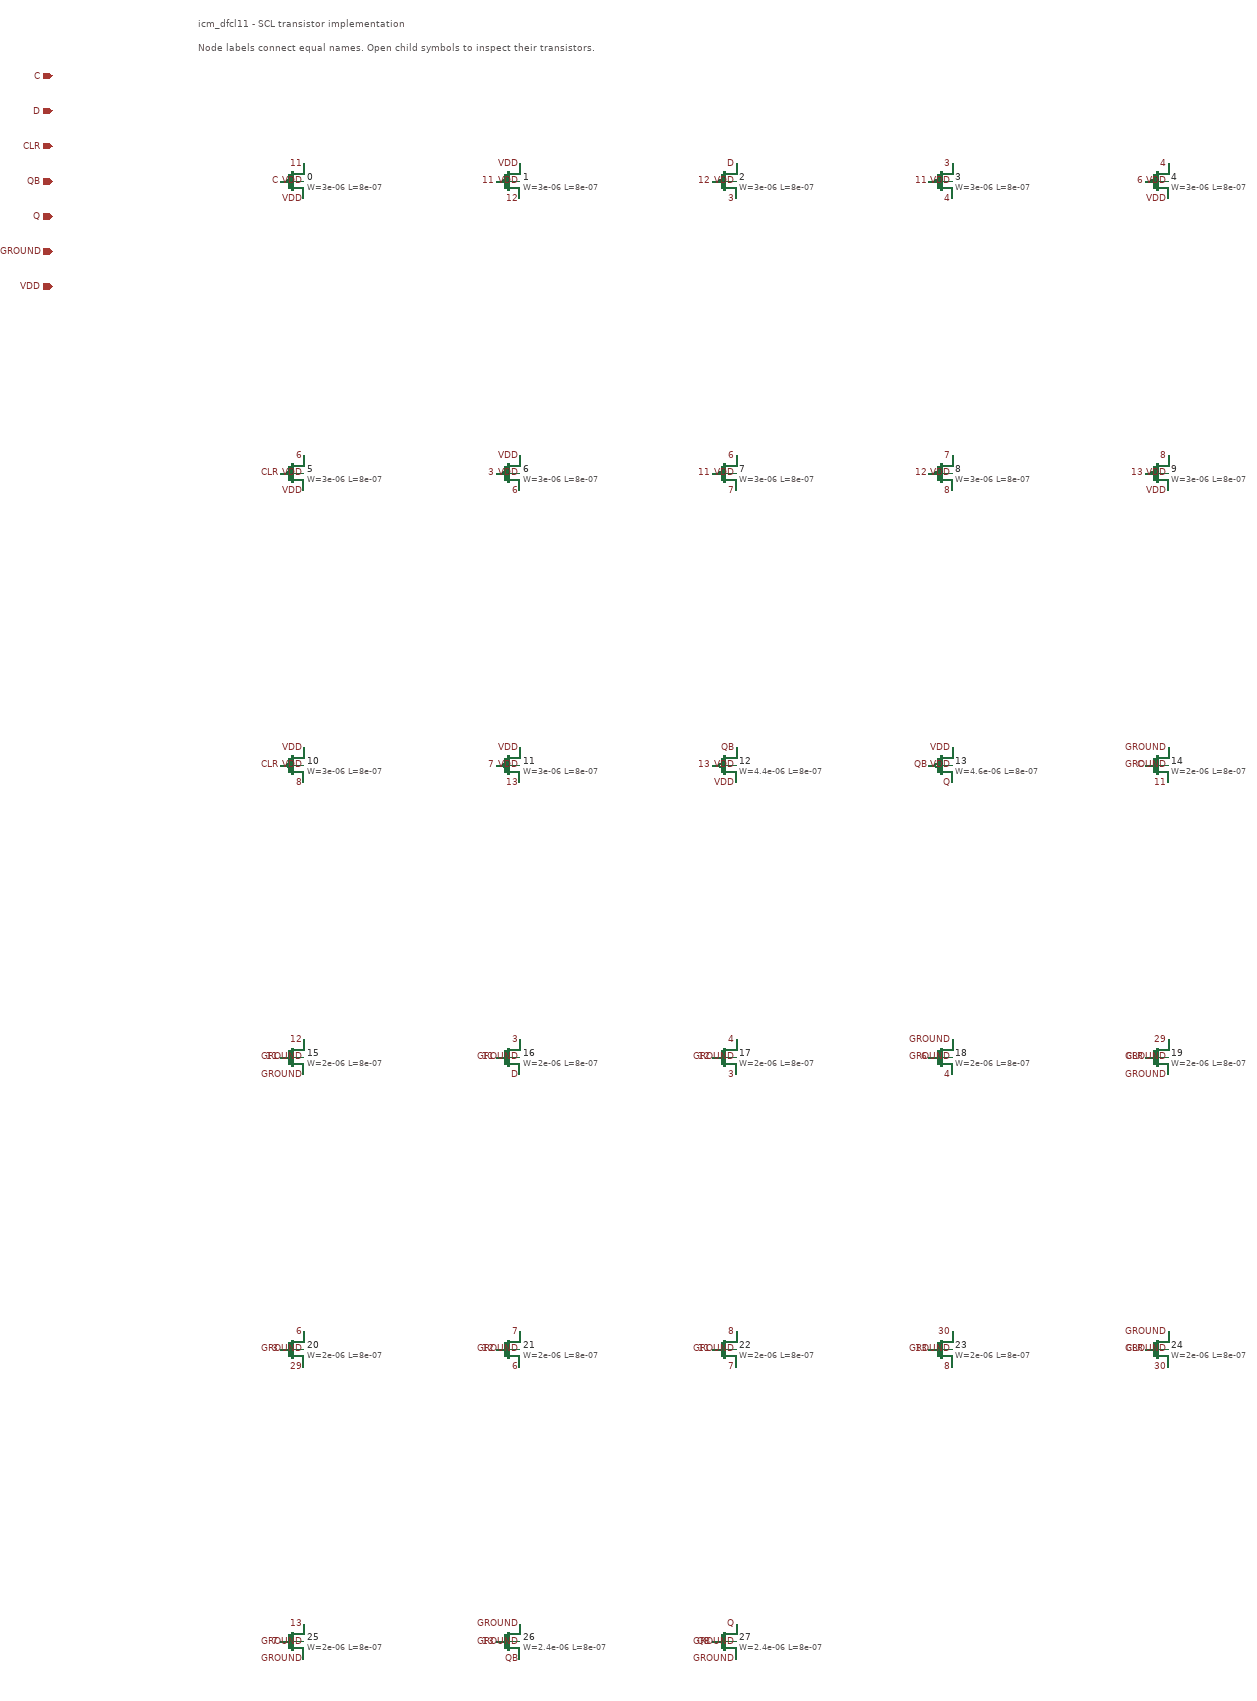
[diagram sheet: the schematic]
v {xschem version=3.4.5 file_version=1.2}
G {}
K {}
V {}
S {}
E {}
T {icm_dfcl11 - SCL transistor implementation} 0 -100 0 0 .5 .5 {}
T {Node labels connect equal names. Open child symbols to inspect their transistors.} 0 -60 0 0 .25 .25 {}
C {/usr/share/xschem/xschem_library/devices/iopin.sym} -250 0 0 0 {name=P0 lab=C}
C {/usr/share/xschem/xschem_library/devices/iopin.sym} -250 60 0 0 {name=P1 lab=D}
C {/usr/share/xschem/xschem_library/devices/iopin.sym} -250 120 0 0 {name=P2 lab=CLR}
C {/usr/share/xschem/xschem_library/devices/iopin.sym} -250 180 0 0 {name=P3 lab=QB}
C {/usr/share/xschem/xschem_library/devices/iopin.sym} -250 240 0 0 {name=P4 lab=Q}
C {/usr/share/xschem/xschem_library/devices/iopin.sym} -250 300 0 0 {name=P5 lab=GROUND}
C {/usr/share/xschem/xschem_library/devices/iopin.sym} -250 360 0 0 {name=P6 lab=VDD}
C {/home/shreyas/open_source_scl_cp8d/open_pdks/scl_cp8d/libs.tech/xschem/scl_pcell/pmos4_p_cp8d.sym} 160 180 0 0 {name=0 model=P W="3e-06" L="8e-07" nf=1 mult="1" ad="9.6e-12" as="8.7e-12" pd="1.24e-05" ps="1.18e-05" nrd=0.366667 nrs=0.533333}
C {/usr/share/xschem/xschem_library/devices/lab_pin.sym} 180 210 0 0 {name=L1 lab=VDD}
C {/usr/share/xschem/xschem_library/devices/lab_pin.sym} 140 180 0 0 {name=L2 lab=C}
C {/usr/share/xschem/xschem_library/devices/lab_pin.sym} 180 150 0 0 {name=L3 lab=11}
C {/usr/share/xschem/xschem_library/devices/lab_pin.sym} 180 180 0 0 {name=L4 lab=VDD}
C {/home/shreyas/open_source_scl_cp8d/open_pdks/scl_cp8d/libs.tech/xschem/scl_pcell/pmos4_p_cp8d.sym} 530 180 0 0 {name=1 model=P W="3e-06" L="8e-07" nf=1 mult="1" ad="8.7e-12" as="9.6e-12" pd="1.18e-05" ps="1.24e-05" nrd=0.366667 nrs=0.533333}
C {/usr/share/xschem/xschem_library/devices/lab_pin.sym} 550 210 0 0 {name=L5 lab=12}
C {/usr/share/xschem/xschem_library/devices/lab_pin.sym} 510 180 0 0 {name=L6 lab=11}
C {/usr/share/xschem/xschem_library/devices/lab_pin.sym} 550 150 0 0 {name=L7 lab=VDD}
C {/usr/share/xschem/xschem_library/devices/lab_pin.sym} 550 180 0 0 {name=L8 lab=VDD}
C {/home/shreyas/open_source_scl_cp8d/open_pdks/scl_cp8d/libs.tech/xschem/scl_pcell/pmos4_p_cp8d.sym} 900 180 0 0 {name=2 model=P W="3e-06" L="8e-07" nf=1 mult="1" ad="1.05e-11" as="8.7e-12" pd="1.3e-05" ps="1.18e-05" nrd=0.391667 nrs=0.533333}
C {/usr/share/xschem/xschem_library/devices/lab_pin.sym} 920 210 0 0 {name=L9 lab=3}
C {/usr/share/xschem/xschem_library/devices/lab_pin.sym} 880 180 0 0 {name=L10 lab=12}
C {/usr/share/xschem/xschem_library/devices/lab_pin.sym} 920 150 0 0 {name=L11 lab=D}
C {/usr/share/xschem/xschem_library/devices/lab_pin.sym} 920 180 0 0 {name=L12 lab=VDD}
C {/home/shreyas/open_source_scl_cp8d/open_pdks/scl_cp8d/libs.tech/xschem/scl_pcell/pmos4_p_cp8d.sym} 1270 180 0 0 {name=3 model=P W="3e-06" L="8e-07" nf=1 mult="1" ad="1.08e-11" as="1.05e-11" pd="1.32e-05" ps="1.3e-05" nrd=0.408333 nrs=0.583333}
C {/usr/share/xschem/xschem_library/devices/lab_pin.sym} 1290 210 0 0 {name=L13 lab=4}
C {/usr/share/xschem/xschem_library/devices/lab_pin.sym} 1250 180 0 0 {name=L14 lab=11}
C {/usr/share/xschem/xschem_library/devices/lab_pin.sym} 1290 150 0 0 {name=L15 lab=3}
C {/usr/share/xschem/xschem_library/devices/lab_pin.sym} 1290 180 0 0 {name=L16 lab=VDD}
C {/home/shreyas/open_source_scl_cp8d/open_pdks/scl_cp8d/libs.tech/xschem/scl_pcell/pmos4_p_cp8d.sym} 1640 180 0 0 {name=4 model=P W="3e-06" L="8e-07" nf=1 mult="1" ad="8.7e-12" as="1.08e-11" pd="1.18e-05" ps="1.32e-05" nrd=0.366667 nrs=0.583333}
C {/usr/share/xschem/xschem_library/devices/lab_pin.sym} 1660 210 0 0 {name=L17 lab=VDD}
C {/usr/share/xschem/xschem_library/devices/lab_pin.sym} 1620 180 0 0 {name=L18 lab=6}
C {/usr/share/xschem/xschem_library/devices/lab_pin.sym} 1660 150 0 0 {name=L19 lab=4}
C {/usr/share/xschem/xschem_library/devices/lab_pin.sym} 1660 180 0 0 {name=L20 lab=VDD}
C {/home/shreyas/open_source_scl_cp8d/open_pdks/scl_cp8d/libs.tech/xschem/scl_pcell/pmos4_p_cp8d.sym} 160 680 0 0 {name=5 model=P W="3e-06" L="8e-07" nf=1 mult="1" ad="9.6e-12" as="8.7e-12" pd="1.24e-05" ps="1.18e-05" nrd=0.366667 nrs=0.533333}
C {/usr/share/xschem/xschem_library/devices/lab_pin.sym} 180 710 0 0 {name=L21 lab=VDD}
C {/usr/share/xschem/xschem_library/devices/lab_pin.sym} 140 680 0 0 {name=L22 lab=CLR}
C {/usr/share/xschem/xschem_library/devices/lab_pin.sym} 180 650 0 0 {name=L23 lab=6}
C {/usr/share/xschem/xschem_library/devices/lab_pin.sym} 180 680 0 0 {name=L24 lab=VDD}
C {/home/shreyas/open_source_scl_cp8d/open_pdks/scl_cp8d/libs.tech/xschem/scl_pcell/pmos4_p_cp8d.sym} 530 680 0 0 {name=6 model=P W="3e-06" L="8e-07" nf=1 mult="1" ad="1.08e-11" as="9.6e-12" pd="1.32e-05" ps="1.24e-05" nrd=0.391667 nrs=0.533333}
C {/usr/share/xschem/xschem_library/devices/lab_pin.sym} 550 710 0 0 {name=L25 lab=6}
C {/usr/share/xschem/xschem_library/devices/lab_pin.sym} 510 680 0 0 {name=L26 lab=3}
C {/usr/share/xschem/xschem_library/devices/lab_pin.sym} 550 650 0 0 {name=L27 lab=VDD}
C {/usr/share/xschem/xschem_library/devices/lab_pin.sym} 550 680 0 0 {name=L28 lab=VDD}
C {/home/shreyas/open_source_scl_cp8d/open_pdks/scl_cp8d/libs.tech/xschem/scl_pcell/pmos4_p_cp8d.sym} 900 680 0 0 {name=7 model=P W="3e-06" L="8e-07" nf=1 mult="1" ad="1.08e-11" as="1.08e-11" pd="1.32e-05" ps="1.32e-05" nrd=0.391667 nrs=0.616667}
C {/usr/share/xschem/xschem_library/devices/lab_pin.sym} 920 710 0 0 {name=L29 lab=7}
C {/usr/share/xschem/xschem_library/devices/lab_pin.sym} 880 680 0 0 {name=L30 lab=11}
C {/usr/share/xschem/xschem_library/devices/lab_pin.sym} 920 650 0 0 {name=L31 lab=6}
C {/usr/share/xschem/xschem_library/devices/lab_pin.sym} 920 680 0 0 {name=L32 lab=VDD}
C {/home/shreyas/open_source_scl_cp8d/open_pdks/scl_cp8d/libs.tech/xschem/scl_pcell/pmos4_p_cp8d.sym} 1270 680 0 0 {name=8 model=P W="3e-06" L="8e-07" nf=1 mult="1" ad="1.05e-11" as="1.08e-11" pd="1.3e-05" ps="1.32e-05" nrd=0.391667 nrs=0.616667}
C {/usr/share/xschem/xschem_library/devices/lab_pin.sym} 1290 710 0 0 {name=L33 lab=8}
C {/usr/share/xschem/xschem_library/devices/lab_pin.sym} 1250 680 0 0 {name=L34 lab=12}
C {/usr/share/xschem/xschem_library/devices/lab_pin.sym} 1290 650 0 0 {name=L35 lab=7}
C {/usr/share/xschem/xschem_library/devices/lab_pin.sym} 1290 680 0 0 {name=L36 lab=VDD}
C {/home/shreyas/open_source_scl_cp8d/open_pdks/scl_cp8d/libs.tech/xschem/scl_pcell/pmos4_p_cp8d.sym} 1640 680 0 0 {name=9 model=P W="3e-06" L="8e-07" nf=1 mult="1" ad="9.6e-12" as="1.05e-11" pd="1.24e-05" ps="1.3e-05" nrd=0.366667 nrs=0.583333}
C {/usr/share/xschem/xschem_library/devices/lab_pin.sym} 1660 710 0 0 {name=L37 lab=VDD}
C {/usr/share/xschem/xschem_library/devices/lab_pin.sym} 1620 680 0 0 {name=L38 lab=13}
C {/usr/share/xschem/xschem_library/devices/lab_pin.sym} 1660 650 0 0 {name=L39 lab=8}
C {/usr/share/xschem/xschem_library/devices/lab_pin.sym} 1660 680 0 0 {name=L40 lab=VDD}
C {/home/shreyas/open_source_scl_cp8d/open_pdks/scl_cp8d/libs.tech/xschem/scl_pcell/pmos4_p_cp8d.sym} 160 1180 0 0 {name=10 model=P W="3e-06" L="8e-07" nf=1 mult="1" ad="8.7e-12" as="9.6e-12" pd="1.18e-05" ps="1.24e-05" nrd=0.366667 nrs=0.533333}
C {/usr/share/xschem/xschem_library/devices/lab_pin.sym} 180 1210 0 0 {name=L41 lab=8}
C {/usr/share/xschem/xschem_library/devices/lab_pin.sym} 140 1180 0 0 {name=L42 lab=CLR}
C {/usr/share/xschem/xschem_library/devices/lab_pin.sym} 180 1150 0 0 {name=L43 lab=VDD}
C {/usr/share/xschem/xschem_library/devices/lab_pin.sym} 180 1180 0 0 {name=L44 lab=VDD}
C {/home/shreyas/open_source_scl_cp8d/open_pdks/scl_cp8d/libs.tech/xschem/scl_pcell/pmos4_p_cp8d.sym} 530 1180 0 0 {name=11 model=P W="3e-06" L="8e-07" nf=1 mult="1" ad="8.7e-12" as="8.7e-12" pd="1.18e-05" ps="1.18e-05" nrd=0.366667 nrs=0.533333}
C {/usr/share/xschem/xschem_library/devices/lab_pin.sym} 550 1210 0 0 {name=L45 lab=13}
C {/usr/share/xschem/xschem_library/devices/lab_pin.sym} 510 1180 0 0 {name=L46 lab=7}
C {/usr/share/xschem/xschem_library/devices/lab_pin.sym} 550 1150 0 0 {name=L47 lab=VDD}
C {/usr/share/xschem/xschem_library/devices/lab_pin.sym} 550 1180 0 0 {name=L48 lab=VDD}
C {/home/shreyas/open_source_scl_cp8d/open_pdks/scl_cp8d/libs.tech/xschem/scl_pcell/pmos4_p_cp8d.sym} 900 1180 0 0 {name=12 model=P W="4.4e-06" L="8e-07" nf=1 mult="1" ad="1.441e-11" as="1.276e-11" pd="1.56e-05" ps="1.46e-05" nrd=0.25 nrs=0.363636}
C {/usr/share/xschem/xschem_library/devices/lab_pin.sym} 920 1210 0 0 {name=L49 lab=VDD}
C {/usr/share/xschem/xschem_library/devices/lab_pin.sym} 880 1180 0 0 {name=L50 lab=13}
C {/usr/share/xschem/xschem_library/devices/lab_pin.sym} 920 1150 0 0 {name=L51 lab=QB}
C {/usr/share/xschem/xschem_library/devices/lab_pin.sym} 920 1180 0 0 {name=L52 lab=VDD}
C {/home/shreyas/open_source_scl_cp8d/open_pdks/scl_cp8d/libs.tech/xschem/scl_pcell/pmos4_p_cp8d.sym} 1270 1180 0 0 {name=13 model=P W="4.6e-06" L="8e-07" nf=1 mult="1" ad="1.334e-11" as="1.441e-11" pd="1.5e-05" ps="1.56e-05" nrd=0.23913 nrs=0.347826}
C {/usr/share/xschem/xschem_library/devices/lab_pin.sym} 1290 1210 0 0 {name=L53 lab=Q}
C {/usr/share/xschem/xschem_library/devices/lab_pin.sym} 1250 1180 0 0 {name=L54 lab=QB}
C {/usr/share/xschem/xschem_library/devices/lab_pin.sym} 1290 1150 0 0 {name=L55 lab=VDD}
C {/usr/share/xschem/xschem_library/devices/lab_pin.sym} 1290 1180 0 0 {name=L56 lab=VDD}
C {/home/shreyas/open_source_scl_cp8d/open_pdks/scl_cp8d/libs.tech/xschem/scl_pcell/nmos4_n_cp8d.sym} 1640 1180 0 0 {name=14 model=N W="2e-06" L="8e-07" nf=1 mult="1" ad="8.24e-12" as="7.5e-12" pd="1.2e-05" ps="1.12e-05" nrd=0.575 nrs=0.85}
C {/usr/share/xschem/xschem_library/devices/lab_pin.sym} 1660 1150 0 0 {name=L57 lab=GROUND}
C {/usr/share/xschem/xschem_library/devices/lab_pin.sym} 1620 1180 0 0 {name=L58 lab=C}
C {/usr/share/xschem/xschem_library/devices/lab_pin.sym} 1660 1210 0 0 {name=L59 lab=11}
C {/usr/share/xschem/xschem_library/devices/lab_pin.sym} 1660 1180 0 0 {name=L60 lab=GROUND}
C {/home/shreyas/open_source_scl_cp8d/open_pdks/scl_cp8d/libs.tech/xschem/scl_pcell/nmos4_n_cp8d.sym} 160 1680 0 0 {name=15 model=N W="2e-06" L="8e-07" nf=1 mult="1" ad="7.5e-12" as="8.24e-12" pd="1.12e-05" ps="1.2e-05" nrd=0.575 nrs=0.85}
C {/usr/share/xschem/xschem_library/devices/lab_pin.sym} 180 1650 0 0 {name=L61 lab=12}
C {/usr/share/xschem/xschem_library/devices/lab_pin.sym} 140 1680 0 0 {name=L62 lab=11}
C {/usr/share/xschem/xschem_library/devices/lab_pin.sym} 180 1710 0 0 {name=L63 lab=GROUND}
C {/usr/share/xschem/xschem_library/devices/lab_pin.sym} 180 1680 0 0 {name=L64 lab=GROUND}
C {/home/shreyas/open_source_scl_cp8d/open_pdks/scl_cp8d/libs.tech/xschem/scl_pcell/nmos4_n_cp8d.sym} 530 1680 0 0 {name=16 model=N W="2e-06" L="8e-07" nf=1 mult="1" ad="8.76e-12" as="7.5e-12" pd="1.24e-05" ps="1.12e-05" nrd=0.6 nrs=0.85}
C {/usr/share/xschem/xschem_library/devices/lab_pin.sym} 550 1650 0 0 {name=L65 lab=3}
C {/usr/share/xschem/xschem_library/devices/lab_pin.sym} 510 1680 0 0 {name=L66 lab=11}
C {/usr/share/xschem/xschem_library/devices/lab_pin.sym} 550 1710 0 0 {name=L67 lab=D}
C {/usr/share/xschem/xschem_library/devices/lab_pin.sym} 550 1680 0 0 {name=L68 lab=GROUND}
C {/home/shreyas/open_source_scl_cp8d/open_pdks/scl_cp8d/libs.tech/xschem/scl_pcell/nmos4_n_cp8d.sym} 900 1680 0 0 {name=17 model=N W="2e-06" L="8e-07" nf=1 mult="1" ad="3.056e-11" as="8.76e-12" pd="2.34e-05" ps="1.24e-05" nrd=0.9 nrs=0.9}
C {/usr/share/xschem/xschem_library/devices/lab_pin.sym} 920 1650 0 0 {name=L69 lab=4}
C {/usr/share/xschem/xschem_library/devices/lab_pin.sym} 880 1680 0 0 {name=L70 lab=12}
C {/usr/share/xschem/xschem_library/devices/lab_pin.sym} 920 1710 0 0 {name=L71 lab=3}
C {/usr/share/xschem/xschem_library/devices/lab_pin.sym} 920 1680 0 0 {name=L72 lab=GROUND}
C {/home/shreyas/open_source_scl_cp8d/open_pdks/scl_cp8d/libs.tech/xschem/scl_pcell/nmos4_n_cp8d.sym} 1270 1680 0 0 {name=18 model=N W="2e-06" L="8e-07" nf=1 mult="1" ad="2.236e-11" as="3.056e-11" pd="2.42e-05" ps="2.34e-05" nrd=0.9 nrs=0.9}
C {/usr/share/xschem/xschem_library/devices/lab_pin.sym} 1290 1650 0 0 {name=L73 lab=GROUND}
C {/usr/share/xschem/xschem_library/devices/lab_pin.sym} 1250 1680 0 0 {name=L74 lab=6}
C {/usr/share/xschem/xschem_library/devices/lab_pin.sym} 1290 1710 0 0 {name=L75 lab=4}
C {/usr/share/xschem/xschem_library/devices/lab_pin.sym} 1290 1680 0 0 {name=L76 lab=GROUND}
C {/home/shreyas/open_source_scl_cp8d/open_pdks/scl_cp8d/libs.tech/xschem/scl_pcell/nmos4_n_cp8d.sym} 1640 1680 0 0 {name=19 model=N W="2e-06" L="8e-07" nf=1 mult="1" ad="3.2e-12" as="2.236e-11" pd="5.2e-06" ps="2.42e-05" nrd=0.8 nrs=0.9}
C {/usr/share/xschem/xschem_library/devices/lab_pin.sym} 1660 1650 0 0 {name=L77 lab=29}
C {/usr/share/xschem/xschem_library/devices/lab_pin.sym} 1620 1680 0 0 {name=L78 lab=CLR}
C {/usr/share/xschem/xschem_library/devices/lab_pin.sym} 1660 1710 0 0 {name=L79 lab=GROUND}
C {/usr/share/xschem/xschem_library/devices/lab_pin.sym} 1660 1680 0 0 {name=L80 lab=GROUND}
C {/home/shreyas/open_source_scl_cp8d/open_pdks/scl_cp8d/libs.tech/xschem/scl_pcell/nmos4_n_cp8d.sym} 160 2180 0 0 {name=20 model=N W="2e-06" L="8e-07" nf=1 mult="1" ad="8.76e-12" as="3.2e-12" pd="1.24e-05" ps="5.2e-06" nrd=0.9 nrs=0.8}
C {/usr/share/xschem/xschem_library/devices/lab_pin.sym} 180 2150 0 0 {name=L81 lab=6}
C {/usr/share/xschem/xschem_library/devices/lab_pin.sym} 140 2180 0 0 {name=L82 lab=3}
C {/usr/share/xschem/xschem_library/devices/lab_pin.sym} 180 2210 0 0 {name=L83 lab=29}
C {/usr/share/xschem/xschem_library/devices/lab_pin.sym} 180 2180 0 0 {name=L84 lab=GROUND}
C {/home/shreyas/open_source_scl_cp8d/open_pdks/scl_cp8d/libs.tech/xschem/scl_pcell/nmos4_n_cp8d.sym} 530 2180 0 0 {name=21 model=N W="2e-06" L="8e-07" nf=1 mult="1" ad="8.76e-12" as="8.76e-12" pd="1.24e-05" ps="1.24e-05" nrd=0.6 nrs=0.9}
C {/usr/share/xschem/xschem_library/devices/lab_pin.sym} 550 2150 0 0 {name=L85 lab=7}
C {/usr/share/xschem/xschem_library/devices/lab_pin.sym} 510 2180 0 0 {name=L86 lab=12}
C {/usr/share/xschem/xschem_library/devices/lab_pin.sym} 550 2210 0 0 {name=L87 lab=6}
C {/usr/share/xschem/xschem_library/devices/lab_pin.sym} 550 2180 0 0 {name=L88 lab=GROUND}
C {/home/shreyas/open_source_scl_cp8d/open_pdks/scl_cp8d/libs.tech/xschem/scl_pcell/nmos4_n_cp8d.sym} 900 2180 0 0 {name=22 model=N W="2e-06" L="8e-07" nf=1 mult="1" ad="2.92e-11" as="8.76e-12" pd="2.3e-05" ps="1.24e-05" nrd=0.9 nrs=0.9}
C {/usr/share/xschem/xschem_library/devices/lab_pin.sym} 920 2150 0 0 {name=L89 lab=8}
C {/usr/share/xschem/xschem_library/devices/lab_pin.sym} 880 2180 0 0 {name=L90 lab=11}
C {/usr/share/xschem/xschem_library/devices/lab_pin.sym} 920 2210 0 0 {name=L91 lab=7}
C {/usr/share/xschem/xschem_library/devices/lab_pin.sym} 920 2180 0 0 {name=L92 lab=GROUND}
C {/home/shreyas/open_source_scl_cp8d/open_pdks/scl_cp8d/libs.tech/xschem/scl_pcell/nmos4_n_cp8d.sym} 1270 2180 0 0 {name=23 model=N W="2e-06" L="8e-07" nf=1 mult="1" ad="4.6e-12" as="2.92e-11" pd="6.6e-06" ps="2.3e-05" nrd=1.15 nrs=0.9}
C {/usr/share/xschem/xschem_library/devices/lab_pin.sym} 1290 2150 0 0 {name=L93 lab=30}
C {/usr/share/xschem/xschem_library/devices/lab_pin.sym} 1250 2180 0 0 {name=L94 lab=13}
C {/usr/share/xschem/xschem_library/devices/lab_pin.sym} 1290 2210 0 0 {name=L95 lab=8}
C {/usr/share/xschem/xschem_library/devices/lab_pin.sym} 1290 2180 0 0 {name=L96 lab=GROUND}
C {/home/shreyas/open_source_scl_cp8d/open_pdks/scl_cp8d/libs.tech/xschem/scl_pcell/nmos4_n_cp8d.sym} 1640 2180 0 0 {name=24 model=N W="2e-06" L="8e-07" nf=1 mult="1" ad="1.962e-11" as="4.6e-12" pd="2.14e-05" ps="6.6e-06" nrd=0.9 nrs=1.15}
C {/usr/share/xschem/xschem_library/devices/lab_pin.sym} 1660 2150 0 0 {name=L97 lab=GROUND}
C {/usr/share/xschem/xschem_library/devices/lab_pin.sym} 1620 2180 0 0 {name=L98 lab=CLR}
C {/usr/share/xschem/xschem_library/devices/lab_pin.sym} 1660 2210 0 0 {name=L99 lab=30}
C {/usr/share/xschem/xschem_library/devices/lab_pin.sym} 1660 2180 0 0 {name=L100 lab=GROUND}
C {/home/shreyas/open_source_scl_cp8d/open_pdks/scl_cp8d/libs.tech/xschem/scl_pcell/nmos4_n_cp8d.sym} 160 2680 0 0 {name=25 model=N W="2e-06" L="8e-07" nf=1 mult="1" ad="7.76e-12" as="1.962e-11" pd="1.14e-05" ps="2.14e-05" nrd=0.9 nrs=0.9}
C {/usr/share/xschem/xschem_library/devices/lab_pin.sym} 180 2650 0 0 {name=L101 lab=13}
C {/usr/share/xschem/xschem_library/devices/lab_pin.sym} 140 2680 0 0 {name=L102 lab=7}
C {/usr/share/xschem/xschem_library/devices/lab_pin.sym} 180 2710 0 0 {name=L103 lab=GROUND}
C {/usr/share/xschem/xschem_library/devices/lab_pin.sym} 180 2680 0 0 {name=L104 lab=GROUND}
C {/home/shreyas/open_source_scl_cp8d/open_pdks/scl_cp8d/libs.tech/xschem/scl_pcell/nmos4_n_cp8d.sym} 530 2680 0 0 {name=26 model=N W="2.4e-06" L="8e-07" nf=1 mult="1" ad="9.16e-12" as="7.96e-12" pd="1.24e-05" ps="1.14e-05" nrd=0.5 nrs=0.75}
C {/usr/share/xschem/xschem_library/devices/lab_pin.sym} 550 2650 0 0 {name=L105 lab=GROUND}
C {/usr/share/xschem/xschem_library/devices/lab_pin.sym} 510 2680 0 0 {name=L106 lab=13}
C {/usr/share/xschem/xschem_library/devices/lab_pin.sym} 550 2710 0 0 {name=L107 lab=QB}
C {/usr/share/xschem/xschem_library/devices/lab_pin.sym} 550 2680 0 0 {name=L108 lab=GROUND}
C {/home/shreyas/open_source_scl_cp8d/open_pdks/scl_cp8d/libs.tech/xschem/scl_pcell/nmos4_n_cp8d.sym} 900 2680 0 0 {name=27 model=N W="2.4e-06" L="8e-07" nf=1 mult="1" ad="7.96e-12" as="9.16e-12" pd="1.14e-05" ps="1.24e-05" nrd=0.5 nrs=0.75}
C {/usr/share/xschem/xschem_library/devices/lab_pin.sym} 920 2650 0 0 {name=L109 lab=Q}
C {/usr/share/xschem/xschem_library/devices/lab_pin.sym} 880 2680 0 0 {name=L110 lab=QB}
C {/usr/share/xschem/xschem_library/devices/lab_pin.sym} 920 2710 0 0 {name=L111 lab=GROUND}
C {/usr/share/xschem/xschem_library/devices/lab_pin.sym} 920 2680 0 0 {name=L112 lab=GROUND}
